VERSION 5.7 ;
  NOWIREEXTENSIONATPIN ON ;
  DIVIDERCHAR "/" ;
  BUSBITCHARS "[]" ;
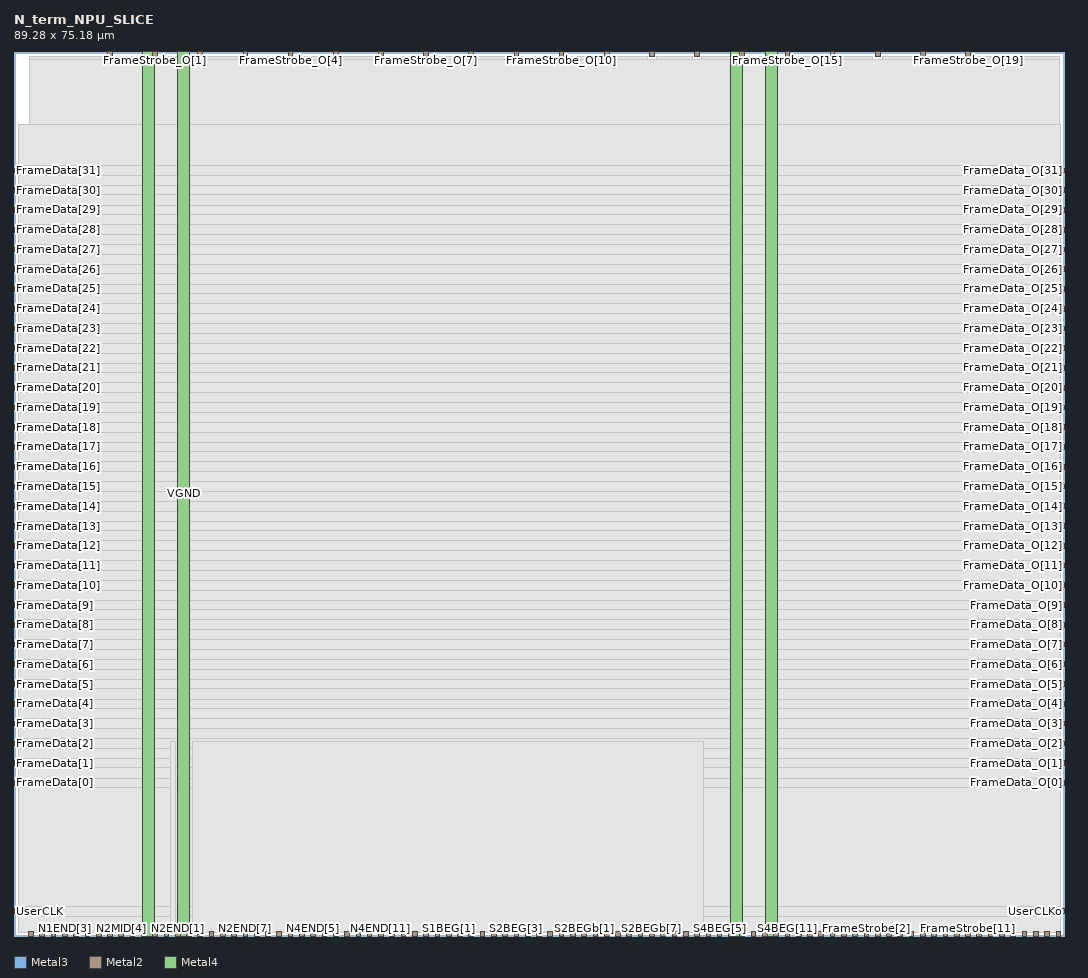
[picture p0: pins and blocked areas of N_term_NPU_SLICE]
MACRO N_term_NPU_SLICE
  CLASS BLOCK ;
  FOREIGN N_term_NPU_SLICE ;
  ORIGIN 0.000 0.000 ;
  SIZE 89.280 BY 75.180 ;
  PIN FrameData[0]
    DIRECTION INPUT ;
    USE SIGNAL ;
    ANTENNAGATEAREA 0.180700 ;
    ANTENNADIFFAREA 2.015400 ;
    PORT
      LAYER Metal3 ;
        RECT 0.000 12.820 0.400 13.220 ;
    END
  END FrameData[0]
  PIN FrameData[10]
    DIRECTION INPUT ;
    USE SIGNAL ;
    ANTENNAGATEAREA 0.180700 ;
    ANTENNADIFFAREA 2.015400 ;
    PORT
      LAYER Metal3 ;
        RECT 0.000 29.620 0.400 30.020 ;
    END
  END FrameData[10]
  PIN FrameData[11]
    DIRECTION INPUT ;
    USE SIGNAL ;
    ANTENNAGATEAREA 0.180700 ;
    ANTENNADIFFAREA 2.015400 ;
    PORT
      LAYER Metal3 ;
        RECT 0.000 31.300 0.400 31.700 ;
    END
  END FrameData[11]
  PIN FrameData[12]
    DIRECTION INPUT ;
    USE SIGNAL ;
    ANTENNAGATEAREA 0.180700 ;
    ANTENNADIFFAREA 2.015400 ;
    PORT
      LAYER Metal3 ;
        RECT 0.000 32.980 0.400 33.380 ;
    END
  END FrameData[12]
  PIN FrameData[13]
    DIRECTION INPUT ;
    USE SIGNAL ;
    ANTENNAGATEAREA 0.180700 ;
    ANTENNADIFFAREA 2.015400 ;
    PORT
      LAYER Metal3 ;
        RECT 0.000 34.660 0.400 35.060 ;
    END
  END FrameData[13]
  PIN FrameData[14]
    DIRECTION INPUT ;
    USE SIGNAL ;
    ANTENNAGATEAREA 0.180700 ;
    ANTENNADIFFAREA 2.015400 ;
    PORT
      LAYER Metal3 ;
        RECT 0.000 36.340 0.400 36.740 ;
    END
  END FrameData[14]
  PIN FrameData[15]
    DIRECTION INPUT ;
    USE SIGNAL ;
    ANTENNAGATEAREA 0.180700 ;
    ANTENNADIFFAREA 2.015400 ;
    PORT
      LAYER Metal3 ;
        RECT 0.000 38.020 0.400 38.420 ;
    END
  END FrameData[15]
  PIN FrameData[16]
    DIRECTION INPUT ;
    USE SIGNAL ;
    ANTENNAGATEAREA 0.180700 ;
    ANTENNADIFFAREA 2.015400 ;
    PORT
      LAYER Metal3 ;
        RECT 0.000 39.700 0.400 40.100 ;
    END
  END FrameData[16]
  PIN FrameData[17]
    DIRECTION INPUT ;
    USE SIGNAL ;
    ANTENNAGATEAREA 0.180700 ;
    ANTENNADIFFAREA 2.015400 ;
    PORT
      LAYER Metal3 ;
        RECT 0.000 41.380 0.400 41.780 ;
    END
  END FrameData[17]
  PIN FrameData[18]
    DIRECTION INPUT ;
    USE SIGNAL ;
    ANTENNAGATEAREA 0.180700 ;
    ANTENNADIFFAREA 2.015400 ;
    PORT
      LAYER Metal3 ;
        RECT 0.000 43.060 0.400 43.460 ;
    END
  END FrameData[18]
  PIN FrameData[19]
    DIRECTION INPUT ;
    USE SIGNAL ;
    ANTENNAGATEAREA 0.180700 ;
    ANTENNADIFFAREA 2.015400 ;
    PORT
      LAYER Metal3 ;
        RECT 0.000 44.740 0.400 45.140 ;
    END
  END FrameData[19]
  PIN FrameData[1]
    DIRECTION INPUT ;
    USE SIGNAL ;
    ANTENNAGATEAREA 0.180700 ;
    ANTENNADIFFAREA 2.015400 ;
    PORT
      LAYER Metal3 ;
        RECT 0.000 14.500 0.400 14.900 ;
    END
  END FrameData[1]
  PIN FrameData[20]
    DIRECTION INPUT ;
    USE SIGNAL ;
    ANTENNAGATEAREA 0.180700 ;
    ANTENNADIFFAREA 2.015400 ;
    PORT
      LAYER Metal3 ;
        RECT 0.000 46.420 0.400 46.820 ;
    END
  END FrameData[20]
  PIN FrameData[21]
    DIRECTION INPUT ;
    USE SIGNAL ;
    ANTENNAGATEAREA 0.180700 ;
    ANTENNADIFFAREA 2.015400 ;
    PORT
      LAYER Metal3 ;
        RECT 0.000 48.100 0.400 48.500 ;
    END
  END FrameData[21]
  PIN FrameData[22]
    DIRECTION INPUT ;
    USE SIGNAL ;
    ANTENNAGATEAREA 0.180700 ;
    ANTENNADIFFAREA 2.015400 ;
    PORT
      LAYER Metal3 ;
        RECT 0.000 49.780 0.400 50.180 ;
    END
  END FrameData[22]
  PIN FrameData[23]
    DIRECTION INPUT ;
    USE SIGNAL ;
    ANTENNAGATEAREA 0.180700 ;
    ANTENNADIFFAREA 2.015400 ;
    PORT
      LAYER Metal3 ;
        RECT 0.000 51.460 0.400 51.860 ;
    END
  END FrameData[23]
  PIN FrameData[24]
    DIRECTION INPUT ;
    USE SIGNAL ;
    ANTENNAGATEAREA 0.180700 ;
    ANTENNADIFFAREA 2.015400 ;
    PORT
      LAYER Metal3 ;
        RECT 0.000 53.140 0.400 53.540 ;
    END
  END FrameData[24]
  PIN FrameData[25]
    DIRECTION INPUT ;
    USE SIGNAL ;
    ANTENNAGATEAREA 0.180700 ;
    ANTENNADIFFAREA 2.015400 ;
    PORT
      LAYER Metal3 ;
        RECT 0.000 54.820 0.400 55.220 ;
    END
  END FrameData[25]
  PIN FrameData[26]
    DIRECTION INPUT ;
    USE SIGNAL ;
    ANTENNAGATEAREA 0.180700 ;
    ANTENNADIFFAREA 2.015400 ;
    PORT
      LAYER Metal3 ;
        RECT 0.000 56.500 0.400 56.900 ;
    END
  END FrameData[26]
  PIN FrameData[27]
    DIRECTION INPUT ;
    USE SIGNAL ;
    ANTENNAGATEAREA 0.180700 ;
    ANTENNADIFFAREA 2.015400 ;
    PORT
      LAYER Metal3 ;
        RECT 0.000 58.180 0.400 58.580 ;
    END
  END FrameData[27]
  PIN FrameData[28]
    DIRECTION INPUT ;
    USE SIGNAL ;
    ANTENNAGATEAREA 0.180700 ;
    ANTENNADIFFAREA 2.015400 ;
    PORT
      LAYER Metal3 ;
        RECT 0.000 59.860 0.400 60.260 ;
    END
  END FrameData[28]
  PIN FrameData[29]
    DIRECTION INPUT ;
    USE SIGNAL ;
    ANTENNAGATEAREA 0.180700 ;
    ANTENNADIFFAREA 2.015400 ;
    PORT
      LAYER Metal3 ;
        RECT 0.000 61.540 0.400 61.940 ;
    END
  END FrameData[29]
  PIN FrameData[2]
    DIRECTION INPUT ;
    USE SIGNAL ;
    ANTENNAGATEAREA 0.180700 ;
    ANTENNADIFFAREA 2.015400 ;
    PORT
      LAYER Metal3 ;
        RECT 0.000 16.180 0.400 16.580 ;
    END
  END FrameData[2]
  PIN FrameData[30]
    DIRECTION INPUT ;
    USE SIGNAL ;
    ANTENNAGATEAREA 0.180700 ;
    ANTENNADIFFAREA 2.015400 ;
    PORT
      LAYER Metal3 ;
        RECT 0.000 63.220 0.400 63.620 ;
    END
  END FrameData[30]
  PIN FrameData[31]
    DIRECTION INPUT ;
    USE SIGNAL ;
    ANTENNAGATEAREA 0.180700 ;
    ANTENNADIFFAREA 2.015400 ;
    PORT
      LAYER Metal3 ;
        RECT 0.000 64.900 0.400 65.300 ;
    END
  END FrameData[31]
  PIN FrameData[3]
    DIRECTION INPUT ;
    USE SIGNAL ;
    ANTENNAGATEAREA 0.180700 ;
    ANTENNADIFFAREA 2.015400 ;
    PORT
      LAYER Metal3 ;
        RECT 0.000 17.860 0.400 18.260 ;
    END
  END FrameData[3]
  PIN FrameData[4]
    DIRECTION INPUT ;
    USE SIGNAL ;
    ANTENNAGATEAREA 0.180700 ;
    ANTENNADIFFAREA 2.015400 ;
    PORT
      LAYER Metal3 ;
        RECT 0.000 19.540 0.400 19.940 ;
    END
  END FrameData[4]
  PIN FrameData[5]
    DIRECTION INPUT ;
    USE SIGNAL ;
    ANTENNAGATEAREA 0.180700 ;
    ANTENNADIFFAREA 2.015400 ;
    PORT
      LAYER Metal3 ;
        RECT 0.000 21.220 0.400 21.620 ;
    END
  END FrameData[5]
  PIN FrameData[6]
    DIRECTION INPUT ;
    USE SIGNAL ;
    ANTENNAGATEAREA 0.180700 ;
    ANTENNADIFFAREA 2.015400 ;
    PORT
      LAYER Metal3 ;
        RECT 0.000 22.900 0.400 23.300 ;
    END
  END FrameData[6]
  PIN FrameData[7]
    DIRECTION INPUT ;
    USE SIGNAL ;
    ANTENNAGATEAREA 0.180700 ;
    ANTENNADIFFAREA 2.015400 ;
    PORT
      LAYER Metal3 ;
        RECT 0.000 24.580 0.400 24.980 ;
    END
  END FrameData[7]
  PIN FrameData[8]
    DIRECTION INPUT ;
    USE SIGNAL ;
    ANTENNAGATEAREA 0.180700 ;
    ANTENNADIFFAREA 2.015400 ;
    PORT
      LAYER Metal3 ;
        RECT 0.000 26.260 0.400 26.660 ;
    END
  END FrameData[8]
  PIN FrameData[9]
    DIRECTION INPUT ;
    USE SIGNAL ;
    ANTENNAGATEAREA 0.180700 ;
    ANTENNADIFFAREA 2.015400 ;
    PORT
      LAYER Metal3 ;
        RECT 0.000 27.940 0.400 28.340 ;
    END
  END FrameData[9]
  PIN FrameData_O[0]
    DIRECTION OUTPUT ;
    USE SIGNAL ;
    ANTENNADIFFAREA 2.724000 ;
    PORT
      LAYER Metal3 ;
        RECT 88.880 12.820 89.280 13.220 ;
    END
  END FrameData_O[0]
  PIN FrameData_O[10]
    DIRECTION OUTPUT ;
    USE SIGNAL ;
    ANTENNADIFFAREA 2.724000 ;
    PORT
      LAYER Metal3 ;
        RECT 88.880 29.620 89.280 30.020 ;
    END
  END FrameData_O[10]
  PIN FrameData_O[11]
    DIRECTION OUTPUT ;
    USE SIGNAL ;
    ANTENNADIFFAREA 2.724000 ;
    PORT
      LAYER Metal3 ;
        RECT 88.880 31.300 89.280 31.700 ;
    END
  END FrameData_O[11]
  PIN FrameData_O[12]
    DIRECTION OUTPUT ;
    USE SIGNAL ;
    ANTENNADIFFAREA 2.724000 ;
    PORT
      LAYER Metal3 ;
        RECT 88.880 32.980 89.280 33.380 ;
    END
  END FrameData_O[12]
  PIN FrameData_O[13]
    DIRECTION OUTPUT ;
    USE SIGNAL ;
    ANTENNADIFFAREA 2.724000 ;
    PORT
      LAYER Metal3 ;
        RECT 88.880 34.660 89.280 35.060 ;
    END
  END FrameData_O[13]
  PIN FrameData_O[14]
    DIRECTION OUTPUT ;
    USE SIGNAL ;
    ANTENNADIFFAREA 2.724000 ;
    PORT
      LAYER Metal3 ;
        RECT 88.880 36.340 89.280 36.740 ;
    END
  END FrameData_O[14]
  PIN FrameData_O[15]
    DIRECTION OUTPUT ;
    USE SIGNAL ;
    ANTENNADIFFAREA 2.724000 ;
    PORT
      LAYER Metal3 ;
        RECT 88.880 38.020 89.280 38.420 ;
    END
  END FrameData_O[15]
  PIN FrameData_O[16]
    DIRECTION OUTPUT ;
    USE SIGNAL ;
    ANTENNADIFFAREA 2.724000 ;
    PORT
      LAYER Metal3 ;
        RECT 88.880 39.700 89.280 40.100 ;
    END
  END FrameData_O[16]
  PIN FrameData_O[17]
    DIRECTION OUTPUT ;
    USE SIGNAL ;
    ANTENNADIFFAREA 2.724000 ;
    PORT
      LAYER Metal3 ;
        RECT 88.880 41.380 89.280 41.780 ;
    END
  END FrameData_O[17]
  PIN FrameData_O[18]
    DIRECTION OUTPUT ;
    USE SIGNAL ;
    ANTENNADIFFAREA 2.724000 ;
    PORT
      LAYER Metal3 ;
        RECT 88.880 43.060 89.280 43.460 ;
    END
  END FrameData_O[18]
  PIN FrameData_O[19]
    DIRECTION OUTPUT ;
    USE SIGNAL ;
    ANTENNADIFFAREA 2.724000 ;
    PORT
      LAYER Metal3 ;
        RECT 88.880 44.740 89.280 45.140 ;
    END
  END FrameData_O[19]
  PIN FrameData_O[1]
    DIRECTION OUTPUT ;
    USE SIGNAL ;
    ANTENNADIFFAREA 2.724000 ;
    PORT
      LAYER Metal3 ;
        RECT 88.880 14.500 89.280 14.900 ;
    END
  END FrameData_O[1]
  PIN FrameData_O[20]
    DIRECTION OUTPUT ;
    USE SIGNAL ;
    ANTENNADIFFAREA 2.724000 ;
    PORT
      LAYER Metal3 ;
        RECT 88.880 46.420 89.280 46.820 ;
    END
  END FrameData_O[20]
  PIN FrameData_O[21]
    DIRECTION OUTPUT ;
    USE SIGNAL ;
    ANTENNADIFFAREA 2.724000 ;
    PORT
      LAYER Metal3 ;
        RECT 88.880 48.100 89.280 48.500 ;
    END
  END FrameData_O[21]
  PIN FrameData_O[22]
    DIRECTION OUTPUT ;
    USE SIGNAL ;
    ANTENNADIFFAREA 2.724000 ;
    PORT
      LAYER Metal3 ;
        RECT 88.880 49.780 89.280 50.180 ;
    END
  END FrameData_O[22]
  PIN FrameData_O[23]
    DIRECTION OUTPUT ;
    USE SIGNAL ;
    ANTENNADIFFAREA 2.724000 ;
    PORT
      LAYER Metal3 ;
        RECT 88.880 51.460 89.280 51.860 ;
    END
  END FrameData_O[23]
  PIN FrameData_O[24]
    DIRECTION OUTPUT ;
    USE SIGNAL ;
    ANTENNADIFFAREA 2.724000 ;
    PORT
      LAYER Metal3 ;
        RECT 88.880 53.140 89.280 53.540 ;
    END
  END FrameData_O[24]
  PIN FrameData_O[25]
    DIRECTION OUTPUT ;
    USE SIGNAL ;
    ANTENNADIFFAREA 2.724000 ;
    PORT
      LAYER Metal3 ;
        RECT 88.880 54.820 89.280 55.220 ;
    END
  END FrameData_O[25]
  PIN FrameData_O[26]
    DIRECTION OUTPUT ;
    USE SIGNAL ;
    ANTENNADIFFAREA 2.724000 ;
    PORT
      LAYER Metal3 ;
        RECT 88.880 56.500 89.280 56.900 ;
    END
  END FrameData_O[26]
  PIN FrameData_O[27]
    DIRECTION OUTPUT ;
    USE SIGNAL ;
    ANTENNADIFFAREA 2.724000 ;
    PORT
      LAYER Metal3 ;
        RECT 88.880 58.180 89.280 58.580 ;
    END
  END FrameData_O[27]
  PIN FrameData_O[28]
    DIRECTION OUTPUT ;
    USE SIGNAL ;
    ANTENNADIFFAREA 2.724000 ;
    PORT
      LAYER Metal3 ;
        RECT 88.880 59.860 89.280 60.260 ;
    END
  END FrameData_O[28]
  PIN FrameData_O[29]
    DIRECTION OUTPUT ;
    USE SIGNAL ;
    ANTENNADIFFAREA 2.724000 ;
    PORT
      LAYER Metal3 ;
        RECT 88.880 61.540 89.280 61.940 ;
    END
  END FrameData_O[29]
  PIN FrameData_O[2]
    DIRECTION OUTPUT ;
    USE SIGNAL ;
    ANTENNADIFFAREA 2.724000 ;
    PORT
      LAYER Metal3 ;
        RECT 88.880 16.180 89.280 16.580 ;
    END
  END FrameData_O[2]
  PIN FrameData_O[30]
    DIRECTION OUTPUT ;
    USE SIGNAL ;
    ANTENNADIFFAREA 2.724000 ;
    PORT
      LAYER Metal3 ;
        RECT 88.880 63.220 89.280 63.620 ;
    END
  END FrameData_O[30]
  PIN FrameData_O[31]
    DIRECTION OUTPUT ;
    USE SIGNAL ;
    ANTENNADIFFAREA 2.724000 ;
    PORT
      LAYER Metal3 ;
        RECT 88.880 64.900 89.280 65.300 ;
    END
  END FrameData_O[31]
  PIN FrameData_O[3]
    DIRECTION OUTPUT ;
    USE SIGNAL ;
    ANTENNADIFFAREA 2.724000 ;
    PORT
      LAYER Metal3 ;
        RECT 88.880 17.860 89.280 18.260 ;
    END
  END FrameData_O[3]
  PIN FrameData_O[4]
    DIRECTION OUTPUT ;
    USE SIGNAL ;
    ANTENNADIFFAREA 2.724000 ;
    PORT
      LAYER Metal3 ;
        RECT 88.880 19.540 89.280 19.940 ;
    END
  END FrameData_O[4]
  PIN FrameData_O[5]
    DIRECTION OUTPUT ;
    USE SIGNAL ;
    ANTENNADIFFAREA 2.724000 ;
    PORT
      LAYER Metal3 ;
        RECT 88.880 21.220 89.280 21.620 ;
    END
  END FrameData_O[5]
  PIN FrameData_O[6]
    DIRECTION OUTPUT ;
    USE SIGNAL ;
    ANTENNADIFFAREA 2.724000 ;
    PORT
      LAYER Metal3 ;
        RECT 88.880 22.900 89.280 23.300 ;
    END
  END FrameData_O[6]
  PIN FrameData_O[7]
    DIRECTION OUTPUT ;
    USE SIGNAL ;
    ANTENNADIFFAREA 2.724000 ;
    PORT
      LAYER Metal3 ;
        RECT 88.880 24.580 89.280 24.980 ;
    END
  END FrameData_O[7]
  PIN FrameData_O[8]
    DIRECTION OUTPUT ;
    USE SIGNAL ;
    ANTENNADIFFAREA 2.724000 ;
    PORT
      LAYER Metal3 ;
        RECT 88.880 26.260 89.280 26.660 ;
    END
  END FrameData_O[8]
  PIN FrameData_O[9]
    DIRECTION OUTPUT ;
    USE SIGNAL ;
    ANTENNADIFFAREA 2.724000 ;
    PORT
      LAYER Metal3 ;
        RECT 88.880 27.940 89.280 28.340 ;
    END
  END FrameData_O[9]
  PIN FrameStrobe[0]
    DIRECTION INPUT ;
    USE SIGNAL ;
    ANTENNAGATEAREA 0.180700 ;
    ANTENNADIFFAREA 2.015400 ;
    PORT
      LAYER Metal2 ;
        RECT 70.360 0.000 70.760 0.400 ;
    END
  END FrameStrobe[0]
  PIN FrameStrobe[10]
    DIRECTION INPUT ;
    USE SIGNAL ;
    ANTENNAGATEAREA 0.180700 ;
    ANTENNADIFFAREA 2.015400 ;
    PORT
      LAYER Metal2 ;
        RECT 79.960 0.000 80.360 0.400 ;
    END
  END FrameStrobe[10]
  PIN FrameStrobe[11]
    DIRECTION INPUT ;
    USE SIGNAL ;
    ANTENNAGATEAREA 0.180700 ;
    ANTENNADIFFAREA 2.015400 ;
    PORT
      LAYER Metal2 ;
        RECT 80.920 0.000 81.320 0.400 ;
    END
  END FrameStrobe[11]
  PIN FrameStrobe[12]
    DIRECTION INPUT ;
    USE SIGNAL ;
    ANTENNAGATEAREA 0.180700 ;
    ANTENNADIFFAREA 2.015400 ;
    PORT
      LAYER Metal2 ;
        RECT 81.880 0.000 82.280 0.400 ;
    END
  END FrameStrobe[12]
  PIN FrameStrobe[13]
    DIRECTION INPUT ;
    USE SIGNAL ;
    ANTENNAGATEAREA 0.180700 ;
    ANTENNADIFFAREA 2.015400 ;
    PORT
      LAYER Metal2 ;
        RECT 82.840 0.000 83.240 0.400 ;
    END
  END FrameStrobe[13]
  PIN FrameStrobe[14]
    DIRECTION INPUT ;
    USE SIGNAL ;
    ANTENNAGATEAREA 0.180700 ;
    ANTENNADIFFAREA 2.015400 ;
    PORT
      LAYER Metal2 ;
        RECT 83.800 0.000 84.200 0.400 ;
    END
  END FrameStrobe[14]
  PIN FrameStrobe[15]
    DIRECTION INPUT ;
    USE SIGNAL ;
    ANTENNAGATEAREA 0.180700 ;
    ANTENNADIFFAREA 2.015400 ;
    PORT
      LAYER Metal2 ;
        RECT 84.760 0.000 85.160 0.400 ;
    END
  END FrameStrobe[15]
  PIN FrameStrobe[16]
    DIRECTION INPUT ;
    USE SIGNAL ;
    ANTENNAGATEAREA 0.180700 ;
    ANTENNADIFFAREA 2.015400 ;
    PORT
      LAYER Metal2 ;
        RECT 85.720 0.000 86.120 0.400 ;
    END
  END FrameStrobe[16]
  PIN FrameStrobe[17]
    DIRECTION INPUT ;
    USE SIGNAL ;
    ANTENNAGATEAREA 0.180700 ;
    ANTENNADIFFAREA 2.015400 ;
    PORT
      LAYER Metal2 ;
        RECT 86.680 0.000 87.080 0.400 ;
    END
  END FrameStrobe[17]
  PIN FrameStrobe[18]
    DIRECTION INPUT ;
    USE SIGNAL ;
    ANTENNAGATEAREA 0.180700 ;
    ANTENNADIFFAREA 2.015400 ;
    PORT
      LAYER Metal2 ;
        RECT 87.640 0.000 88.040 0.400 ;
    END
  END FrameStrobe[18]
  PIN FrameStrobe[19]
    DIRECTION INPUT ;
    USE SIGNAL ;
    ANTENNAGATEAREA 0.180700 ;
    ANTENNADIFFAREA 2.015400 ;
    PORT
      LAYER Metal2 ;
        RECT 88.600 0.000 89.000 0.400 ;
    END
  END FrameStrobe[19]
  PIN FrameStrobe[1]
    DIRECTION INPUT ;
    USE SIGNAL ;
    ANTENNAGATEAREA 0.180700 ;
    ANTENNADIFFAREA 2.015400 ;
    PORT
      LAYER Metal2 ;
        RECT 71.320 0.000 71.720 0.400 ;
    END
  END FrameStrobe[1]
  PIN FrameStrobe[2]
    DIRECTION INPUT ;
    USE SIGNAL ;
    ANTENNAGATEAREA 0.180700 ;
    ANTENNADIFFAREA 2.015400 ;
    PORT
      LAYER Metal2 ;
        RECT 72.280 0.000 72.680 0.400 ;
    END
  END FrameStrobe[2]
  PIN FrameStrobe[3]
    DIRECTION INPUT ;
    USE SIGNAL ;
    ANTENNAGATEAREA 0.180700 ;
    ANTENNADIFFAREA 2.015400 ;
    PORT
      LAYER Metal2 ;
        RECT 73.240 0.000 73.640 0.400 ;
    END
  END FrameStrobe[3]
  PIN FrameStrobe[4]
    DIRECTION INPUT ;
    USE SIGNAL ;
    ANTENNAGATEAREA 0.180700 ;
    ANTENNADIFFAREA 2.015400 ;
    PORT
      LAYER Metal2 ;
        RECT 74.200 0.000 74.600 0.400 ;
    END
  END FrameStrobe[4]
  PIN FrameStrobe[5]
    DIRECTION INPUT ;
    USE SIGNAL ;
    ANTENNAGATEAREA 0.180700 ;
    ANTENNADIFFAREA 2.015400 ;
    PORT
      LAYER Metal2 ;
        RECT 75.160 0.000 75.560 0.400 ;
    END
  END FrameStrobe[5]
  PIN FrameStrobe[6]
    DIRECTION INPUT ;
    USE SIGNAL ;
    ANTENNAGATEAREA 0.180700 ;
    ANTENNADIFFAREA 2.015400 ;
    PORT
      LAYER Metal2 ;
        RECT 76.120 0.000 76.520 0.400 ;
    END
  END FrameStrobe[6]
  PIN FrameStrobe[7]
    DIRECTION INPUT ;
    USE SIGNAL ;
    ANTENNAGATEAREA 0.180700 ;
    ANTENNADIFFAREA 2.015400 ;
    PORT
      LAYER Metal2 ;
        RECT 77.080 0.000 77.480 0.400 ;
    END
  END FrameStrobe[7]
  PIN FrameStrobe[8]
    DIRECTION INPUT ;
    USE SIGNAL ;
    ANTENNAGATEAREA 0.180700 ;
    ANTENNADIFFAREA 2.015400 ;
    PORT
      LAYER Metal2 ;
        RECT 78.040 0.000 78.440 0.400 ;
    END
  END FrameStrobe[8]
  PIN FrameStrobe[9]
    DIRECTION INPUT ;
    USE SIGNAL ;
    ANTENNAGATEAREA 0.180700 ;
    ANTENNADIFFAREA 2.015400 ;
    PORT
      LAYER Metal2 ;
        RECT 79.000 0.000 79.400 0.400 ;
    END
  END FrameStrobe[9]
  PIN FrameStrobe_O[0]
    DIRECTION OUTPUT ;
    USE SIGNAL ;
    ANTENNADIFFAREA 2.724000 ;
    PORT
      LAYER Metal2 ;
        RECT 7.960 74.780 8.360 75.180 ;
    END
  END FrameStrobe_O[0]
  PIN FrameStrobe_O[10]
    DIRECTION OUTPUT ;
    USE SIGNAL ;
    ANTENNADIFFAREA 2.724000 ;
    PORT
      LAYER Metal2 ;
        RECT 46.360 74.780 46.760 75.180 ;
    END
  END FrameStrobe_O[10]
  PIN FrameStrobe_O[11]
    DIRECTION OUTPUT ;
    USE SIGNAL ;
    ANTENNADIFFAREA 2.724000 ;
    PORT
      LAYER Metal2 ;
        RECT 50.200 74.780 50.600 75.180 ;
    END
  END FrameStrobe_O[11]
  PIN FrameStrobe_O[12]
    DIRECTION OUTPUT ;
    USE SIGNAL ;
    ANTENNADIFFAREA 2.724000 ;
    PORT
      LAYER Metal2 ;
        RECT 54.040 74.780 54.440 75.180 ;
    END
  END FrameStrobe_O[12]
  PIN FrameStrobe_O[13]
    DIRECTION OUTPUT ;
    USE SIGNAL ;
    ANTENNADIFFAREA 2.724000 ;
    PORT
      LAYER Metal2 ;
        RECT 57.880 74.780 58.280 75.180 ;
    END
  END FrameStrobe_O[13]
  PIN FrameStrobe_O[14]
    DIRECTION OUTPUT ;
    USE SIGNAL ;
    ANTENNADIFFAREA 2.724000 ;
    PORT
      LAYER Metal2 ;
        RECT 61.720 74.780 62.120 75.180 ;
    END
  END FrameStrobe_O[14]
  PIN FrameStrobe_O[15]
    DIRECTION OUTPUT ;
    USE SIGNAL ;
    ANTENNADIFFAREA 2.724000 ;
    PORT
      LAYER Metal2 ;
        RECT 65.560 74.780 65.960 75.180 ;
    END
  END FrameStrobe_O[15]
  PIN FrameStrobe_O[16]
    DIRECTION OUTPUT ;
    USE SIGNAL ;
    ANTENNADIFFAREA 2.724000 ;
    PORT
      LAYER Metal2 ;
        RECT 69.400 74.780 69.800 75.180 ;
    END
  END FrameStrobe_O[16]
  PIN FrameStrobe_O[17]
    DIRECTION OUTPUT ;
    USE SIGNAL ;
    ANTENNADIFFAREA 2.724000 ;
    PORT
      LAYER Metal2 ;
        RECT 73.240 74.780 73.640 75.180 ;
    END
  END FrameStrobe_O[17]
  PIN FrameStrobe_O[18]
    DIRECTION OUTPUT ;
    USE SIGNAL ;
    ANTENNADIFFAREA 2.724000 ;
    PORT
      LAYER Metal2 ;
        RECT 77.080 74.780 77.480 75.180 ;
    END
  END FrameStrobe_O[18]
  PIN FrameStrobe_O[19]
    DIRECTION OUTPUT ;
    USE SIGNAL ;
    ANTENNADIFFAREA 2.724000 ;
    PORT
      LAYER Metal2 ;
        RECT 80.920 74.780 81.320 75.180 ;
    END
  END FrameStrobe_O[19]
  PIN FrameStrobe_O[1]
    DIRECTION OUTPUT ;
    USE SIGNAL ;
    ANTENNADIFFAREA 2.724000 ;
    PORT
      LAYER Metal2 ;
        RECT 11.800 74.780 12.200 75.180 ;
    END
  END FrameStrobe_O[1]
  PIN FrameStrobe_O[2]
    DIRECTION OUTPUT ;
    USE SIGNAL ;
    ANTENNADIFFAREA 2.724000 ;
    PORT
      LAYER Metal2 ;
        RECT 15.640 74.780 16.040 75.180 ;
    END
  END FrameStrobe_O[2]
  PIN FrameStrobe_O[3]
    DIRECTION OUTPUT ;
    USE SIGNAL ;
    ANTENNADIFFAREA 2.724000 ;
    PORT
      LAYER Metal2 ;
        RECT 19.480 74.780 19.880 75.180 ;
    END
  END FrameStrobe_O[3]
  PIN FrameStrobe_O[4]
    DIRECTION OUTPUT ;
    USE SIGNAL ;
    ANTENNADIFFAREA 2.724000 ;
    PORT
      LAYER Metal2 ;
        RECT 23.320 74.780 23.720 75.180 ;
    END
  END FrameStrobe_O[4]
  PIN FrameStrobe_O[5]
    DIRECTION OUTPUT ;
    USE SIGNAL ;
    ANTENNADIFFAREA 2.724000 ;
    PORT
      LAYER Metal2 ;
        RECT 27.160 74.780 27.560 75.180 ;
    END
  END FrameStrobe_O[5]
  PIN FrameStrobe_O[6]
    DIRECTION OUTPUT ;
    USE SIGNAL ;
    ANTENNADIFFAREA 2.724000 ;
    PORT
      LAYER Metal2 ;
        RECT 31.000 74.780 31.400 75.180 ;
    END
  END FrameStrobe_O[6]
  PIN FrameStrobe_O[7]
    DIRECTION OUTPUT ;
    USE SIGNAL ;
    ANTENNADIFFAREA 2.724000 ;
    PORT
      LAYER Metal2 ;
        RECT 34.840 74.780 35.240 75.180 ;
    END
  END FrameStrobe_O[7]
  PIN FrameStrobe_O[8]
    DIRECTION OUTPUT ;
    USE SIGNAL ;
    ANTENNADIFFAREA 2.724000 ;
    PORT
      LAYER Metal2 ;
        RECT 38.680 74.780 39.080 75.180 ;
    END
  END FrameStrobe_O[8]
  PIN FrameStrobe_O[9]
    DIRECTION OUTPUT ;
    USE SIGNAL ;
    ANTENNADIFFAREA 2.724000 ;
    PORT
      LAYER Metal2 ;
        RECT 42.520 74.780 42.920 75.180 ;
    END
  END FrameStrobe_O[9]
  PIN N1END[0]
    DIRECTION INPUT ;
    USE SIGNAL ;
    ANTENNAGATEAREA 0.180700 ;
    ANTENNADIFFAREA 2.015400 ;
    PORT
      LAYER Metal2 ;
        RECT 1.240 0.000 1.640 0.400 ;
    END
  END N1END[0]
  PIN N1END[1]
    DIRECTION INPUT ;
    USE SIGNAL ;
    ANTENNAGATEAREA 0.180700 ;
    ANTENNADIFFAREA 2.015400 ;
    PORT
      LAYER Metal2 ;
        RECT 2.200 0.000 2.600 0.400 ;
    END
  END N1END[1]
  PIN N1END[2]
    DIRECTION INPUT ;
    USE SIGNAL ;
    ANTENNAGATEAREA 0.180700 ;
    ANTENNADIFFAREA 2.015400 ;
    PORT
      LAYER Metal2 ;
        RECT 3.160 0.000 3.560 0.400 ;
    END
  END N1END[2]
  PIN N1END[3]
    DIRECTION INPUT ;
    USE SIGNAL ;
    ANTENNAGATEAREA 0.180700 ;
    ANTENNADIFFAREA 2.015400 ;
    PORT
      LAYER Metal2 ;
        RECT 4.120 0.000 4.520 0.400 ;
    END
  END N1END[3]
  PIN N2END[0]
    DIRECTION INPUT ;
    USE SIGNAL ;
    ANTENNAGATEAREA 0.180700 ;
    ANTENNADIFFAREA 2.015400 ;
    PORT
      LAYER Metal2 ;
        RECT 12.760 0.000 13.160 0.400 ;
    END
  END N2END[0]
  PIN N2END[1]
    DIRECTION INPUT ;
    USE SIGNAL ;
    ANTENNAGATEAREA 0.180700 ;
    ANTENNADIFFAREA 2.015400 ;
    PORT
      LAYER Metal2 ;
        RECT 13.720 0.000 14.120 0.400 ;
    END
  END N2END[1]
  PIN N2END[2]
    DIRECTION INPUT ;
    USE SIGNAL ;
    ANTENNAGATEAREA 0.180700 ;
    ANTENNADIFFAREA 2.015400 ;
    PORT
      LAYER Metal2 ;
        RECT 14.680 0.000 15.080 0.400 ;
    END
  END N2END[2]
  PIN N2END[3]
    DIRECTION INPUT ;
    USE SIGNAL ;
    ANTENNAGATEAREA 0.180700 ;
    ANTENNADIFFAREA 2.015400 ;
    PORT
      LAYER Metal2 ;
        RECT 15.640 0.000 16.040 0.400 ;
    END
  END N2END[3]
  PIN N2END[4]
    DIRECTION INPUT ;
    USE SIGNAL ;
    ANTENNAGATEAREA 0.180700 ;
    ANTENNADIFFAREA 2.015400 ;
    PORT
      LAYER Metal2 ;
        RECT 16.600 0.000 17.000 0.400 ;
    END
  END N2END[4]
  PIN N2END[5]
    DIRECTION INPUT ;
    USE SIGNAL ;
    ANTENNAGATEAREA 0.180700 ;
    ANTENNADIFFAREA 2.015400 ;
    PORT
      LAYER Metal2 ;
        RECT 17.560 0.000 17.960 0.400 ;
    END
  END N2END[5]
  PIN N2END[6]
    DIRECTION INPUT ;
    USE SIGNAL ;
    ANTENNAGATEAREA 0.180700 ;
    ANTENNADIFFAREA 2.015400 ;
    PORT
      LAYER Metal2 ;
        RECT 18.520 0.000 18.920 0.400 ;
    END
  END N2END[6]
  PIN N2END[7]
    DIRECTION INPUT ;
    USE SIGNAL ;
    ANTENNAGATEAREA 0.180700 ;
    ANTENNADIFFAREA 2.015400 ;
    PORT
      LAYER Metal2 ;
        RECT 19.480 0.000 19.880 0.400 ;
    END
  END N2END[7]
  PIN N2MID[0]
    DIRECTION INPUT ;
    USE SIGNAL ;
    ANTENNAGATEAREA 0.180700 ;
    ANTENNADIFFAREA 2.015400 ;
    PORT
      LAYER Metal2 ;
        RECT 5.080 0.000 5.480 0.400 ;
    END
  END N2MID[0]
  PIN N2MID[1]
    DIRECTION INPUT ;
    USE SIGNAL ;
    ANTENNAGATEAREA 0.180700 ;
    ANTENNADIFFAREA 2.015400 ;
    PORT
      LAYER Metal2 ;
        RECT 6.040 0.000 6.440 0.400 ;
    END
  END N2MID[1]
  PIN N2MID[2]
    DIRECTION INPUT ;
    USE SIGNAL ;
    ANTENNAGATEAREA 0.180700 ;
    ANTENNADIFFAREA 2.015400 ;
    PORT
      LAYER Metal2 ;
        RECT 7.000 0.000 7.400 0.400 ;
    END
  END N2MID[2]
  PIN N2MID[3]
    DIRECTION INPUT ;
    USE SIGNAL ;
    ANTENNAGATEAREA 0.180700 ;
    ANTENNADIFFAREA 2.015400 ;
    PORT
      LAYER Metal2 ;
        RECT 7.960 0.000 8.360 0.400 ;
    END
  END N2MID[3]
  PIN N2MID[4]
    DIRECTION INPUT ;
    USE SIGNAL ;
    ANTENNAGATEAREA 0.180700 ;
    ANTENNADIFFAREA 2.015400 ;
    PORT
      LAYER Metal2 ;
        RECT 8.920 0.000 9.320 0.400 ;
    END
  END N2MID[4]
  PIN N2MID[5]
    DIRECTION INPUT ;
    USE SIGNAL ;
    ANTENNAGATEAREA 0.180700 ;
    ANTENNADIFFAREA 2.015400 ;
    PORT
      LAYER Metal2 ;
        RECT 9.880 0.000 10.280 0.400 ;
    END
  END N2MID[5]
  PIN N2MID[6]
    DIRECTION INPUT ;
    USE SIGNAL ;
    ANTENNAGATEAREA 0.180700 ;
    ANTENNADIFFAREA 2.015400 ;
    PORT
      LAYER Metal2 ;
        RECT 10.840 0.000 11.240 0.400 ;
    END
  END N2MID[6]
  PIN N2MID[7]
    DIRECTION INPUT ;
    USE SIGNAL ;
    ANTENNAGATEAREA 0.180700 ;
    ANTENNADIFFAREA 2.015400 ;
    PORT
      LAYER Metal2 ;
        RECT 11.800 0.000 12.200 0.400 ;
    END
  END N2MID[7]
  PIN N4END[0]
    DIRECTION INPUT ;
    USE SIGNAL ;
    ANTENNAGATEAREA 0.180700 ;
    ANTENNADIFFAREA 2.015400 ;
    PORT
      LAYER Metal2 ;
        RECT 20.440 0.000 20.840 0.400 ;
    END
  END N4END[0]
  PIN N4END[10]
    DIRECTION INPUT ;
    USE SIGNAL ;
    ANTENNAGATEAREA 0.180700 ;
    ANTENNADIFFAREA 2.015400 ;
    PORT
      LAYER Metal2 ;
        RECT 30.040 0.000 30.440 0.400 ;
    END
  END N4END[10]
  PIN N4END[11]
    DIRECTION INPUT ;
    USE SIGNAL ;
    ANTENNAGATEAREA 0.180700 ;
    ANTENNADIFFAREA 2.015400 ;
    PORT
      LAYER Metal2 ;
        RECT 31.000 0.000 31.400 0.400 ;
    END
  END N4END[11]
  PIN N4END[12]
    DIRECTION INPUT ;
    USE SIGNAL ;
    ANTENNAGATEAREA 0.180700 ;
    ANTENNADIFFAREA 2.015400 ;
    PORT
      LAYER Metal2 ;
        RECT 31.960 0.000 32.360 0.400 ;
    END
  END N4END[12]
  PIN N4END[13]
    DIRECTION INPUT ;
    USE SIGNAL ;
    ANTENNAGATEAREA 0.180700 ;
    ANTENNADIFFAREA 2.015400 ;
    PORT
      LAYER Metal2 ;
        RECT 32.920 0.000 33.320 0.400 ;
    END
  END N4END[13]
  PIN N4END[14]
    DIRECTION INPUT ;
    USE SIGNAL ;
    ANTENNAGATEAREA 0.180700 ;
    ANTENNADIFFAREA 2.015400 ;
    PORT
      LAYER Metal2 ;
        RECT 33.880 0.000 34.280 0.400 ;
    END
  END N4END[14]
  PIN N4END[15]
    DIRECTION INPUT ;
    USE SIGNAL ;
    ANTENNAGATEAREA 0.180700 ;
    ANTENNADIFFAREA 2.015400 ;
    PORT
      LAYER Metal2 ;
        RECT 34.840 0.000 35.240 0.400 ;
    END
  END N4END[15]
  PIN N4END[1]
    DIRECTION INPUT ;
    USE SIGNAL ;
    ANTENNAGATEAREA 0.180700 ;
    ANTENNADIFFAREA 2.015400 ;
    PORT
      LAYER Metal2 ;
        RECT 21.400 0.000 21.800 0.400 ;
    END
  END N4END[1]
  PIN N4END[2]
    DIRECTION INPUT ;
    USE SIGNAL ;
    ANTENNAGATEAREA 0.180700 ;
    ANTENNADIFFAREA 2.015400 ;
    PORT
      LAYER Metal2 ;
        RECT 22.360 0.000 22.760 0.400 ;
    END
  END N4END[2]
  PIN N4END[3]
    DIRECTION INPUT ;
    USE SIGNAL ;
    ANTENNAGATEAREA 0.180700 ;
    ANTENNADIFFAREA 2.015400 ;
    PORT
      LAYER Metal2 ;
        RECT 23.320 0.000 23.720 0.400 ;
    END
  END N4END[3]
  PIN N4END[4]
    DIRECTION INPUT ;
    USE SIGNAL ;
    ANTENNAGATEAREA 0.180700 ;
    ANTENNADIFFAREA 2.015400 ;
    PORT
      LAYER Metal2 ;
        RECT 24.280 0.000 24.680 0.400 ;
    END
  END N4END[4]
  PIN N4END[5]
    DIRECTION INPUT ;
    USE SIGNAL ;
    ANTENNAGATEAREA 0.180700 ;
    ANTENNADIFFAREA 2.015400 ;
    PORT
      LAYER Metal2 ;
        RECT 25.240 0.000 25.640 0.400 ;
    END
  END N4END[5]
  PIN N4END[6]
    DIRECTION INPUT ;
    USE SIGNAL ;
    ANTENNAGATEAREA 0.180700 ;
    ANTENNADIFFAREA 2.015400 ;
    PORT
      LAYER Metal2 ;
        RECT 26.200 0.000 26.600 0.400 ;
    END
  END N4END[6]
  PIN N4END[7]
    DIRECTION INPUT ;
    USE SIGNAL ;
    ANTENNAGATEAREA 0.180700 ;
    ANTENNADIFFAREA 2.015400 ;
    PORT
      LAYER Metal2 ;
        RECT 27.160 0.000 27.560 0.400 ;
    END
  END N4END[7]
  PIN N4END[8]
    DIRECTION INPUT ;
    USE SIGNAL ;
    ANTENNAGATEAREA 0.180700 ;
    ANTENNADIFFAREA 2.015400 ;
    PORT
      LAYER Metal2 ;
        RECT 28.120 0.000 28.520 0.400 ;
    END
  END N4END[8]
  PIN N4END[9]
    DIRECTION INPUT ;
    USE SIGNAL ;
    ANTENNAGATEAREA 0.180700 ;
    ANTENNADIFFAREA 2.015400 ;
    PORT
      LAYER Metal2 ;
        RECT 29.080 0.000 29.480 0.400 ;
    END
  END N4END[9]
  PIN S1BEG[0]
    DIRECTION OUTPUT ;
    USE SIGNAL ;
    ANTENNADIFFAREA 2.724000 ;
    PORT
      LAYER Metal2 ;
        RECT 35.800 0.000 36.200 0.400 ;
    END
  END S1BEG[0]
  PIN S1BEG[1]
    DIRECTION OUTPUT ;
    USE SIGNAL ;
    ANTENNADIFFAREA 2.724000 ;
    PORT
      LAYER Metal2 ;
        RECT 36.760 0.000 37.160 0.400 ;
    END
  END S1BEG[1]
  PIN S1BEG[2]
    DIRECTION OUTPUT ;
    USE SIGNAL ;
    ANTENNADIFFAREA 2.724000 ;
    PORT
      LAYER Metal2 ;
        RECT 37.720 0.000 38.120 0.400 ;
    END
  END S1BEG[2]
  PIN S1BEG[3]
    DIRECTION OUTPUT ;
    USE SIGNAL ;
    ANTENNADIFFAREA 2.724000 ;
    PORT
      LAYER Metal2 ;
        RECT 38.680 0.000 39.080 0.400 ;
    END
  END S1BEG[3]
  PIN S2BEG[0]
    DIRECTION OUTPUT ;
    USE SIGNAL ;
    ANTENNADIFFAREA 2.724000 ;
    PORT
      LAYER Metal2 ;
        RECT 39.640 0.000 40.040 0.400 ;
    END
  END S2BEG[0]
  PIN S2BEG[1]
    DIRECTION OUTPUT ;
    USE SIGNAL ;
    ANTENNADIFFAREA 2.724000 ;
    PORT
      LAYER Metal2 ;
        RECT 40.600 0.000 41.000 0.400 ;
    END
  END S2BEG[1]
  PIN S2BEG[2]
    DIRECTION OUTPUT ;
    USE SIGNAL ;
    ANTENNADIFFAREA 2.724000 ;
    PORT
      LAYER Metal2 ;
        RECT 41.560 0.000 41.960 0.400 ;
    END
  END S2BEG[2]
  PIN S2BEG[3]
    DIRECTION OUTPUT ;
    USE SIGNAL ;
    ANTENNADIFFAREA 2.724000 ;
    PORT
      LAYER Metal2 ;
        RECT 42.520 0.000 42.920 0.400 ;
    END
  END S2BEG[3]
  PIN S2BEG[4]
    DIRECTION OUTPUT ;
    USE SIGNAL ;
    ANTENNADIFFAREA 2.724000 ;
    PORT
      LAYER Metal2 ;
        RECT 43.480 0.000 43.880 0.400 ;
    END
  END S2BEG[4]
  PIN S2BEG[5]
    DIRECTION OUTPUT ;
    USE SIGNAL ;
    ANTENNADIFFAREA 2.724000 ;
    PORT
      LAYER Metal2 ;
        RECT 44.440 0.000 44.840 0.400 ;
    END
  END S2BEG[5]
  PIN S2BEG[6]
    DIRECTION OUTPUT ;
    USE SIGNAL ;
    ANTENNADIFFAREA 2.724000 ;
    PORT
      LAYER Metal2 ;
        RECT 45.400 0.000 45.800 0.400 ;
    END
  END S2BEG[6]
  PIN S2BEG[7]
    DIRECTION OUTPUT ;
    USE SIGNAL ;
    ANTENNADIFFAREA 2.724000 ;
    PORT
      LAYER Metal2 ;
        RECT 46.360 0.000 46.760 0.400 ;
    END
  END S2BEG[7]
  PIN S2BEGb[0]
    DIRECTION OUTPUT ;
    USE SIGNAL ;
    ANTENNADIFFAREA 2.724000 ;
    PORT
      LAYER Metal2 ;
        RECT 47.320 0.000 47.720 0.400 ;
    END
  END S2BEGb[0]
  PIN S2BEGb[1]
    DIRECTION OUTPUT ;
    USE SIGNAL ;
    ANTENNADIFFAREA 2.724000 ;
    PORT
      LAYER Metal2 ;
        RECT 48.280 0.000 48.680 0.400 ;
    END
  END S2BEGb[1]
  PIN S2BEGb[2]
    DIRECTION OUTPUT ;
    USE SIGNAL ;
    ANTENNADIFFAREA 2.724000 ;
    PORT
      LAYER Metal2 ;
        RECT 49.240 0.000 49.640 0.400 ;
    END
  END S2BEGb[2]
  PIN S2BEGb[3]
    DIRECTION OUTPUT ;
    USE SIGNAL ;
    ANTENNADIFFAREA 2.724000 ;
    PORT
      LAYER Metal2 ;
        RECT 50.200 0.000 50.600 0.400 ;
    END
  END S2BEGb[3]
  PIN S2BEGb[4]
    DIRECTION OUTPUT ;
    USE SIGNAL ;
    ANTENNADIFFAREA 2.724000 ;
    PORT
      LAYER Metal2 ;
        RECT 51.160 0.000 51.560 0.400 ;
    END
  END S2BEGb[4]
  PIN S2BEGb[5]
    DIRECTION OUTPUT ;
    USE SIGNAL ;
    ANTENNADIFFAREA 2.724000 ;
    PORT
      LAYER Metal2 ;
        RECT 52.120 0.000 52.520 0.400 ;
    END
  END S2BEGb[5]
  PIN S2BEGb[6]
    DIRECTION OUTPUT ;
    USE SIGNAL ;
    ANTENNADIFFAREA 2.724000 ;
    PORT
      LAYER Metal2 ;
        RECT 53.080 0.000 53.480 0.400 ;
    END
  END S2BEGb[6]
  PIN S2BEGb[7]
    DIRECTION OUTPUT ;
    USE SIGNAL ;
    ANTENNADIFFAREA 2.724000 ;
    PORT
      LAYER Metal2 ;
        RECT 54.040 0.000 54.440 0.400 ;
    END
  END S2BEGb[7]
  PIN S4BEG[0]
    DIRECTION OUTPUT ;
    USE SIGNAL ;
    ANTENNADIFFAREA 2.724000 ;
    PORT
      LAYER Metal2 ;
        RECT 55.000 0.000 55.400 0.400 ;
    END
  END S4BEG[0]
  PIN S4BEG[10]
    DIRECTION OUTPUT ;
    USE SIGNAL ;
    ANTENNADIFFAREA 2.724000 ;
    PORT
      LAYER Metal2 ;
        RECT 64.600 0.000 65.000 0.400 ;
    END
  END S4BEG[10]
  PIN S4BEG[11]
    DIRECTION OUTPUT ;
    USE SIGNAL ;
    ANTENNADIFFAREA 2.724000 ;
    PORT
      LAYER Metal2 ;
        RECT 65.560 0.000 65.960 0.400 ;
    END
  END S4BEG[11]
  PIN S4BEG[12]
    DIRECTION OUTPUT ;
    USE SIGNAL ;
    ANTENNADIFFAREA 2.724000 ;
    PORT
      LAYER Metal2 ;
        RECT 66.520 0.000 66.920 0.400 ;
    END
  END S4BEG[12]
  PIN S4BEG[13]
    DIRECTION OUTPUT ;
    USE SIGNAL ;
    ANTENNADIFFAREA 2.724000 ;
    PORT
      LAYER Metal2 ;
        RECT 67.480 0.000 67.880 0.400 ;
    END
  END S4BEG[13]
  PIN S4BEG[14]
    DIRECTION OUTPUT ;
    USE SIGNAL ;
    ANTENNADIFFAREA 2.724000 ;
    PORT
      LAYER Metal2 ;
        RECT 68.440 0.000 68.840 0.400 ;
    END
  END S4BEG[14]
  PIN S4BEG[15]
    DIRECTION OUTPUT ;
    USE SIGNAL ;
    ANTENNADIFFAREA 2.724000 ;
    PORT
      LAYER Metal2 ;
        RECT 69.400 0.000 69.800 0.400 ;
    END
  END S4BEG[15]
  PIN S4BEG[1]
    DIRECTION OUTPUT ;
    USE SIGNAL ;
    ANTENNADIFFAREA 2.724000 ;
    PORT
      LAYER Metal2 ;
        RECT 55.960 0.000 56.360 0.400 ;
    END
  END S4BEG[1]
  PIN S4BEG[2]
    DIRECTION OUTPUT ;
    USE SIGNAL ;
    ANTENNADIFFAREA 2.724000 ;
    PORT
      LAYER Metal2 ;
        RECT 56.920 0.000 57.320 0.400 ;
    END
  END S4BEG[2]
  PIN S4BEG[3]
    DIRECTION OUTPUT ;
    USE SIGNAL ;
    ANTENNADIFFAREA 2.724000 ;
    PORT
      LAYER Metal2 ;
        RECT 57.880 0.000 58.280 0.400 ;
    END
  END S4BEG[3]
  PIN S4BEG[4]
    DIRECTION OUTPUT ;
    USE SIGNAL ;
    ANTENNADIFFAREA 2.724000 ;
    PORT
      LAYER Metal2 ;
        RECT 58.840 0.000 59.240 0.400 ;
    END
  END S4BEG[4]
  PIN S4BEG[5]
    DIRECTION OUTPUT ;
    USE SIGNAL ;
    ANTENNADIFFAREA 2.724000 ;
    PORT
      LAYER Metal2 ;
        RECT 59.800 0.000 60.200 0.400 ;
    END
  END S4BEG[5]
  PIN S4BEG[6]
    DIRECTION OUTPUT ;
    USE SIGNAL ;
    ANTENNADIFFAREA 2.724000 ;
    PORT
      LAYER Metal2 ;
        RECT 60.760 0.000 61.160 0.400 ;
    END
  END S4BEG[6]
  PIN S4BEG[7]
    DIRECTION OUTPUT ;
    USE SIGNAL ;
    ANTENNADIFFAREA 2.724000 ;
    PORT
      LAYER Metal2 ;
        RECT 61.720 0.000 62.120 0.400 ;
    END
  END S4BEG[7]
  PIN S4BEG[8]
    DIRECTION OUTPUT ;
    USE SIGNAL ;
    ANTENNADIFFAREA 2.724000 ;
    PORT
      LAYER Metal2 ;
        RECT 62.680 0.000 63.080 0.400 ;
    END
  END S4BEG[8]
  PIN S4BEG[9]
    DIRECTION OUTPUT ;
    USE SIGNAL ;
    ANTENNADIFFAREA 2.724000 ;
    PORT
      LAYER Metal2 ;
        RECT 63.640 0.000 64.040 0.400 ;
    END
  END S4BEG[9]
  PIN UserCLK
    DIRECTION INPUT ;
    USE SIGNAL ;
    ANTENNAGATEAREA 1.450800 ;
    PORT
      LAYER Metal3 ;
        RECT 0.000 1.900 0.400 2.300 ;
    END
  END UserCLK
  PIN UserCLKo
    DIRECTION OUTPUT ;
    USE SIGNAL ;
    ANTENNADIFFAREA 2.724000 ;
    PORT
      LAYER Metal3 ;
        RECT 88.880 1.900 89.280 2.300 ;
    END
  END UserCLKo
  PIN VGND
    DIRECTION INOUT ;
    USE GROUND ;
    PORT
      LAYER Metal4 ;
        RECT 13.940 0.000 14.940 75.180 ;
    END
    PORT
      LAYER Metal4 ;
        RECT 63.940 0.000 64.940 75.180 ;
    END
  END VGND
  PIN VPWR
    DIRECTION INOUT ;
    USE POWER ;
    PORT
      LAYER Metal4 ;
        RECT 10.940 0.000 11.940 75.180 ;
    END
    PORT
      LAYER Metal4 ;
        RECT 60.940 0.000 61.940 75.180 ;
    END
  END VPWR
  OBS
      LAYER GatPoly ;
        RECT 1.440 3.630 87.840 68.190 ;
      LAYER Metal1 ;
        RECT 1.440 3.560 87.840 68.260 ;
      LAYER Metal2 ;
        RECT 1.340 74.570 7.750 74.780 ;
        RECT 8.570 74.570 11.590 74.780 ;
        RECT 12.410 74.570 15.430 74.780 ;
        RECT 16.250 74.570 19.270 74.780 ;
        RECT 20.090 74.570 23.110 74.780 ;
        RECT 23.930 74.570 26.950 74.780 ;
        RECT 27.770 74.570 30.790 74.780 ;
        RECT 31.610 74.570 34.630 74.780 ;
        RECT 35.450 74.570 38.470 74.780 ;
        RECT 39.290 74.570 42.310 74.780 ;
        RECT 43.130 74.570 46.150 74.780 ;
        RECT 46.970 74.570 49.990 74.780 ;
        RECT 50.810 74.570 53.830 74.780 ;
        RECT 54.650 74.570 57.670 74.780 ;
        RECT 58.490 74.570 61.510 74.780 ;
        RECT 62.330 74.570 65.350 74.780 ;
        RECT 66.170 74.570 69.190 74.780 ;
        RECT 70.010 74.570 73.030 74.780 ;
        RECT 73.850 74.570 76.870 74.780 ;
        RECT 77.690 74.570 80.710 74.780 ;
        RECT 81.530 74.570 88.905 74.780 ;
        RECT 1.340 0.610 88.905 74.570 ;
        RECT 1.850 0.400 1.990 0.610 ;
        RECT 2.810 0.400 2.950 0.610 ;
        RECT 3.770 0.400 3.910 0.610 ;
        RECT 4.730 0.400 4.870 0.610 ;
        RECT 5.690 0.400 5.830 0.610 ;
        RECT 6.650 0.400 6.790 0.610 ;
        RECT 7.610 0.400 7.750 0.610 ;
        RECT 8.570 0.400 8.710 0.610 ;
        RECT 9.530 0.400 9.670 0.610 ;
        RECT 10.490 0.400 10.630 0.610 ;
        RECT 11.450 0.400 11.590 0.610 ;
        RECT 12.410 0.400 12.550 0.610 ;
        RECT 13.370 0.400 13.510 0.610 ;
        RECT 14.330 0.400 14.470 0.610 ;
        RECT 15.290 0.400 15.430 0.610 ;
        RECT 16.250 0.400 16.390 0.610 ;
        RECT 17.210 0.400 17.350 0.610 ;
        RECT 18.170 0.400 18.310 0.610 ;
        RECT 19.130 0.400 19.270 0.610 ;
        RECT 20.090 0.400 20.230 0.610 ;
        RECT 21.050 0.400 21.190 0.610 ;
        RECT 22.010 0.400 22.150 0.610 ;
        RECT 22.970 0.400 23.110 0.610 ;
        RECT 23.930 0.400 24.070 0.610 ;
        RECT 24.890 0.400 25.030 0.610 ;
        RECT 25.850 0.400 25.990 0.610 ;
        RECT 26.810 0.400 26.950 0.610 ;
        RECT 27.770 0.400 27.910 0.610 ;
        RECT 28.730 0.400 28.870 0.610 ;
        RECT 29.690 0.400 29.830 0.610 ;
        RECT 30.650 0.400 30.790 0.610 ;
        RECT 31.610 0.400 31.750 0.610 ;
        RECT 32.570 0.400 32.710 0.610 ;
        RECT 33.530 0.400 33.670 0.610 ;
        RECT 34.490 0.400 34.630 0.610 ;
        RECT 35.450 0.400 35.590 0.610 ;
        RECT 36.410 0.400 36.550 0.610 ;
        RECT 37.370 0.400 37.510 0.610 ;
        RECT 38.330 0.400 38.470 0.610 ;
        RECT 39.290 0.400 39.430 0.610 ;
        RECT 40.250 0.400 40.390 0.610 ;
        RECT 41.210 0.400 41.350 0.610 ;
        RECT 42.170 0.400 42.310 0.610 ;
        RECT 43.130 0.400 43.270 0.610 ;
        RECT 44.090 0.400 44.230 0.610 ;
        RECT 45.050 0.400 45.190 0.610 ;
        RECT 46.010 0.400 46.150 0.610 ;
        RECT 46.970 0.400 47.110 0.610 ;
        RECT 47.930 0.400 48.070 0.610 ;
        RECT 48.890 0.400 49.030 0.610 ;
        RECT 49.850 0.400 49.990 0.610 ;
        RECT 50.810 0.400 50.950 0.610 ;
        RECT 51.770 0.400 51.910 0.610 ;
        RECT 52.730 0.400 52.870 0.610 ;
        RECT 53.690 0.400 53.830 0.610 ;
        RECT 54.650 0.400 54.790 0.610 ;
        RECT 55.610 0.400 55.750 0.610 ;
        RECT 56.570 0.400 56.710 0.610 ;
        RECT 57.530 0.400 57.670 0.610 ;
        RECT 58.490 0.400 58.630 0.610 ;
        RECT 59.450 0.400 59.590 0.610 ;
        RECT 60.410 0.400 60.550 0.610 ;
        RECT 61.370 0.400 61.510 0.610 ;
        RECT 62.330 0.400 62.470 0.610 ;
        RECT 63.290 0.400 63.430 0.610 ;
        RECT 64.250 0.400 64.390 0.610 ;
        RECT 65.210 0.400 65.350 0.610 ;
        RECT 66.170 0.400 66.310 0.610 ;
        RECT 67.130 0.400 67.270 0.610 ;
        RECT 68.090 0.400 68.230 0.610 ;
        RECT 69.050 0.400 69.190 0.610 ;
        RECT 70.010 0.400 70.150 0.610 ;
        RECT 70.970 0.400 71.110 0.610 ;
        RECT 71.930 0.400 72.070 0.610 ;
        RECT 72.890 0.400 73.030 0.610 ;
        RECT 73.850 0.400 73.990 0.610 ;
        RECT 74.810 0.400 74.950 0.610 ;
        RECT 75.770 0.400 75.910 0.610 ;
        RECT 76.730 0.400 76.870 0.610 ;
        RECT 77.690 0.400 77.830 0.610 ;
        RECT 78.650 0.400 78.790 0.610 ;
        RECT 79.610 0.400 79.750 0.610 ;
        RECT 80.570 0.400 80.710 0.610 ;
        RECT 81.530 0.400 81.670 0.610 ;
        RECT 82.490 0.400 82.630 0.610 ;
        RECT 83.450 0.400 83.590 0.610 ;
        RECT 84.410 0.400 84.550 0.610 ;
        RECT 85.370 0.400 85.510 0.610 ;
        RECT 86.330 0.400 86.470 0.610 ;
        RECT 87.290 0.400 87.430 0.610 ;
        RECT 88.250 0.400 88.390 0.610 ;
      LAYER Metal3 ;
        RECT 0.380 65.510 88.945 68.980 ;
        RECT 0.610 64.690 88.670 65.510 ;
        RECT 0.380 63.830 88.945 64.690 ;
        RECT 0.610 63.010 88.670 63.830 ;
        RECT 0.380 62.150 88.945 63.010 ;
        RECT 0.610 61.330 88.670 62.150 ;
        RECT 0.380 60.470 88.945 61.330 ;
        RECT 0.610 59.650 88.670 60.470 ;
        RECT 0.380 58.790 88.945 59.650 ;
        RECT 0.610 57.970 88.670 58.790 ;
        RECT 0.380 57.110 88.945 57.970 ;
        RECT 0.610 56.290 88.670 57.110 ;
        RECT 0.380 55.430 88.945 56.290 ;
        RECT 0.610 54.610 88.670 55.430 ;
        RECT 0.380 53.750 88.945 54.610 ;
        RECT 0.610 52.930 88.670 53.750 ;
        RECT 0.380 52.070 88.945 52.930 ;
        RECT 0.610 51.250 88.670 52.070 ;
        RECT 0.380 50.390 88.945 51.250 ;
        RECT 0.610 49.570 88.670 50.390 ;
        RECT 0.380 48.710 88.945 49.570 ;
        RECT 0.610 47.890 88.670 48.710 ;
        RECT 0.380 47.030 88.945 47.890 ;
        RECT 0.610 46.210 88.670 47.030 ;
        RECT 0.380 45.350 88.945 46.210 ;
        RECT 0.610 44.530 88.670 45.350 ;
        RECT 0.380 43.670 88.945 44.530 ;
        RECT 0.610 42.850 88.670 43.670 ;
        RECT 0.380 41.990 88.945 42.850 ;
        RECT 0.610 41.170 88.670 41.990 ;
        RECT 0.380 40.310 88.945 41.170 ;
        RECT 0.610 39.490 88.670 40.310 ;
        RECT 0.380 38.630 88.945 39.490 ;
        RECT 0.610 37.810 88.670 38.630 ;
        RECT 0.380 36.950 88.945 37.810 ;
        RECT 0.610 36.130 88.670 36.950 ;
        RECT 0.380 35.270 88.945 36.130 ;
        RECT 0.610 34.450 88.670 35.270 ;
        RECT 0.380 33.590 88.945 34.450 ;
        RECT 0.610 32.770 88.670 33.590 ;
        RECT 0.380 31.910 88.945 32.770 ;
        RECT 0.610 31.090 88.670 31.910 ;
        RECT 0.380 30.230 88.945 31.090 ;
        RECT 0.610 29.410 88.670 30.230 ;
        RECT 0.380 28.550 88.945 29.410 ;
        RECT 0.610 27.730 88.670 28.550 ;
        RECT 0.380 26.870 88.945 27.730 ;
        RECT 0.610 26.050 88.670 26.870 ;
        RECT 0.380 25.190 88.945 26.050 ;
        RECT 0.610 24.370 88.670 25.190 ;
        RECT 0.380 23.510 88.945 24.370 ;
        RECT 0.610 22.690 88.670 23.510 ;
        RECT 0.380 21.830 88.945 22.690 ;
        RECT 0.610 21.010 88.670 21.830 ;
        RECT 0.380 20.150 88.945 21.010 ;
        RECT 0.610 19.330 88.670 20.150 ;
        RECT 0.380 18.470 88.945 19.330 ;
        RECT 0.610 17.650 88.670 18.470 ;
        RECT 0.380 16.790 88.945 17.650 ;
        RECT 0.610 15.970 88.670 16.790 ;
        RECT 0.380 15.110 88.945 15.970 ;
        RECT 0.610 14.290 88.670 15.110 ;
        RECT 0.380 13.430 88.945 14.290 ;
        RECT 0.610 12.610 88.670 13.430 ;
        RECT 0.380 2.510 88.945 12.610 ;
        RECT 0.610 1.690 88.670 2.510 ;
        RECT 0.380 0.315 88.945 1.690 ;
      LAYER Metal4 ;
        RECT 13.340 0.275 13.730 16.525 ;
        RECT 15.150 0.275 58.660 16.525 ;
  END
END N_term_NPU_SLICE
END LIBRARY

